One B-rep face of a CAD part: STEP entity #1502.
In plain terms, the planar face has unit normal (1, 0, 0).
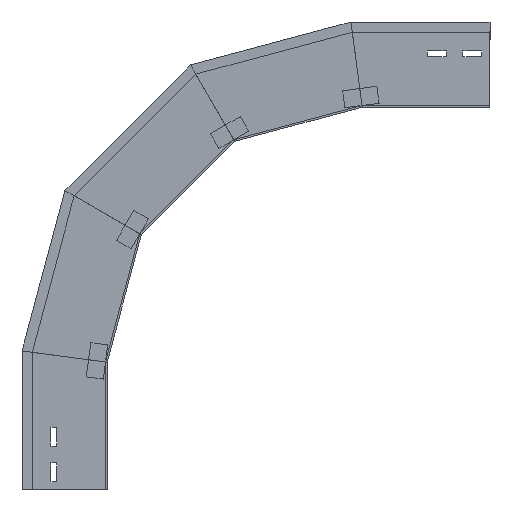
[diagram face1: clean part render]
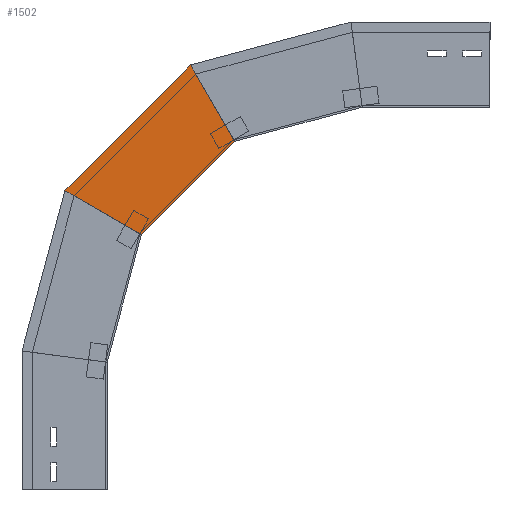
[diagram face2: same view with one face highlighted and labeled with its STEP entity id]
Its self-contained STEP definition (entity closure, numbers rounded to 3 decimals):
#4 = CARTESIAN_POINT ( 'NONE',  ( 0., 49.541, 351.482 ) ) ;
#32 = LINE ( 'NONE', #767, #582 ) ;
#88 = VECTOR ( 'NONE', #998, 1000. ) ;
#174 = CARTESIAN_POINT ( 'NONE',  ( 0., -149.719, 409.32 ) ) ;
#207 = VECTOR ( 'NONE', #1624, 1000. ) ;
#214 = LINE ( 'NONE', #1670, #1814 ) ;
#232 = PLANE ( 'NONE',  #268 ) ;
#243 = VERTEX_POINT ( 'NONE', #864 ) ;
#260 = FACE_OUTER_BOUND ( 'NONE', #607, .T. ) ;
#266 = LINE ( 'NONE', #1582, #88 ) ;
#268 = AXIS2_PLACEMENT_3D ( 'NONE', #683, #1739, #1579 ) ;
#285 = VERTEX_POINT ( 'NONE', #572 ) ;
#341 = EDGE_CURVE ( 'NONE', #243, #1151, #1652, .T. ) ;
#567 = EDGE_CURVE ( 'NONE', #285, #1151, #266, .T. ) ;
#572 = CARTESIAN_POINT ( 'NONE',  ( 0., -97.955, 498.978 ) ) ;
#582 = VECTOR ( 'NONE', #608, 1000. ) ;
#607 = EDGE_LOOP ( 'NONE', ( #1687, #868, #660, #937 ) ) ;
#608 = DIRECTION ( 'NONE',  ( 0., -0.707, 0.707 ) ) ;
#660 = ORIENTED_EDGE ( 'NONE', *, *, #341, .F. ) ;
#683 = CARTESIAN_POINT ( 'NONE',  ( 0., -19.205, 278.806 ) ) ;
#745 = VERTEX_POINT ( 'NONE', #4 ) ;
#767 = CARTESIAN_POINT ( 'NONE',  ( 0., 51.506, 349.517 ) ) ;
#812 = DIRECTION ( 'NONE',  ( 0., -0.866, -0.5 ) ) ;
#864 = CARTESIAN_POINT ( 'NONE',  ( 0., -40.117, 299.719 ) ) ;
#868 = ORIENTED_EDGE ( 'NONE', *, *, #567, .T. ) ;
#904 = EDGE_CURVE ( 'NONE', #745, #243, #214, .T. ) ;
#937 = ORIENTED_EDGE ( 'NONE', *, *, #904, .F. ) ;
#998 = DIRECTION ( 'NONE',  ( 0., -0.5, -0.866 ) ) ;
#1044 = CARTESIAN_POINT ( 'NONE',  ( 0., -19.205, 278.806 ) ) ;
#1151 = VERTEX_POINT ( 'NONE', #174 ) ;
#1174 = EDGE_CURVE ( 'NONE', #745, #285, #32, .T. ) ;
#1502 = ADVANCED_FACE ( 'NONE', ( #260 ), #232, .T. ) ;
#1579 = DIRECTION ( 'NONE',  ( 0., 0., -1. ) ) ;
#1582 = CARTESIAN_POINT ( 'NONE',  ( 0., -173.604, 367.949 ) ) ;
#1624 = DIRECTION ( 'NONE',  ( 0., -0.707, 0.707 ) ) ;
#1652 = LINE ( 'NONE', #1044, #207 ) ;
#1670 = CARTESIAN_POINT ( 'NONE',  ( 0., -78.128, 277.773 ) ) ;
#1687 = ORIENTED_EDGE ( 'NONE', *, *, #1174, .T. ) ;
#1739 = DIRECTION ( 'NONE',  ( 1., 0., 0. ) ) ;
#1814 = VECTOR ( 'NONE', #812, 1000. ) ;
